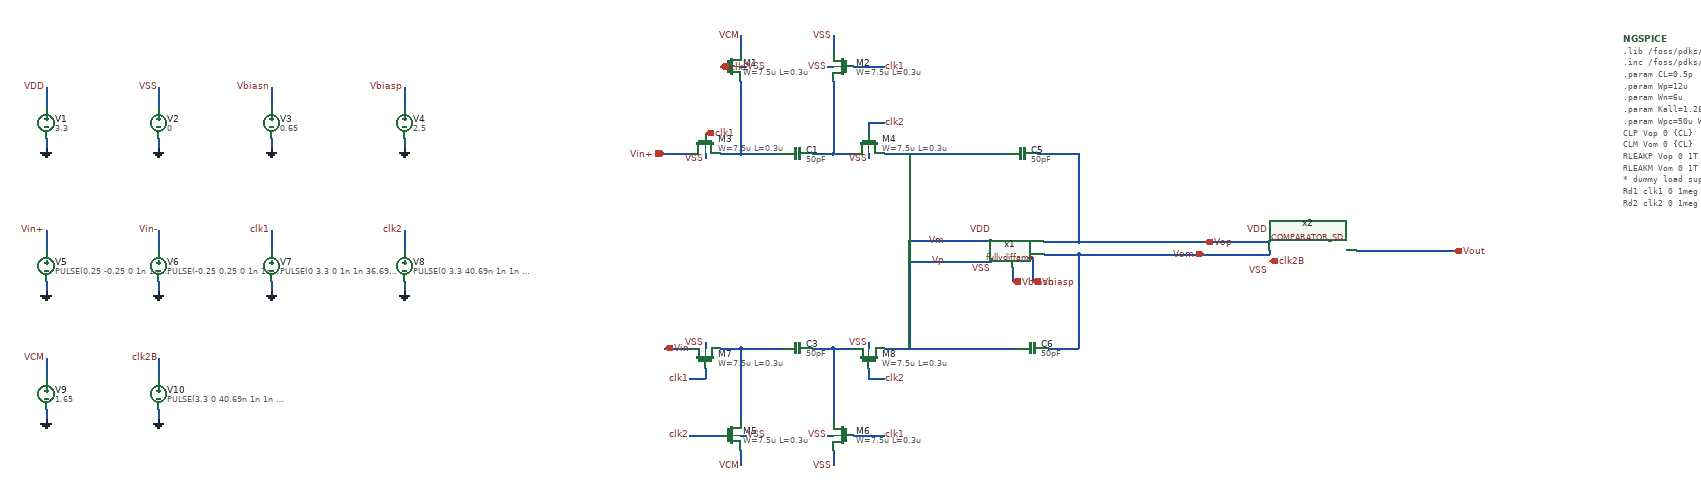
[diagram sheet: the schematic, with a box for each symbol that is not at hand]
v {xschem version=3.4.8RC file_version=1.3}
G {}
K {}
V {}
S {}
F {}
E {}
N 260 -943.75 260 -803.75 {lab=#net1}
N 220 -803.75 260 -803.75 {lab=#net1}
N 260 -803.75 340 -803.75 {lab=#net1}
N 400 -803.75 440 -803.75 {lab=#net2}
N 440 -943.75 440 -803.75 {lab=#net2}
N 440 -803.75 480 -803.75 {lab=#net2}
N 540 -803.75 580 -803.75 {lab=Vm}
N 140 -803.75 160 -803.75 {lab=Vin+}
N 110 -803.75 140 -803.75 {lab=Vin+}
N 510 -863.75 510 -843.75 {lab=clk2}
N 510 -863.75 540 -863.75 {lab=clk2}
N 480 -973.75 540 -973.75 {lab=clk1}
N 440 -1033.75 440 -1003.75 {lab=VSS}
N 260 -1033.75 260 -1003.75 {lab=VCM}
N 260 -423.75 260 -283.75 {lab=#net3}
N 220 -423.75 260 -423.75 {lab=#net3}
N 260 -423.75 340 -423.75 {lab=#net3}
N 400 -423.75 440 -423.75 {lab=#net4}
N 440 -423.75 440 -283.75 {lab=#net4}
N 440 -423.75 480 -423.75 {lab=#net4}
N 540 -423.75 580 -423.75 {lab=Vp}
N 140 -423.75 160 -423.75 {lab=Vin-}
N 110 -423.75 140 -423.75 {lab=Vin-}
N 190 -383.75 190 -363.75 {lab=clk1}
N 160 -363.75 190 -363.75 {lab=clk1}
N 160 -253.75 220 -253.75 {lab=clk2}
N 510 -383.75 510 -363.75 {lab=clk2}
N 510 -363.75 540 -363.75 {lab=clk2}
N 480 -253.75 540 -253.75 {lab=clk1}
N 440 -223.75 440 -193.75 {lab=VSS}
N 260 -223.75 260 -193.75 {lab=VCM}
N 260 -973.75 270 -973.75 {lab=VSS}
N 430 -973.75 440 -973.75 {lab=VSS}
N 190 -803.75 190 -793.75 {lab=VSS}
N 510 -803.75 510 -793.75 {lab=VSS}
N 190 -433.75 190 -423.75 {lab=VSS}
N 510 -433.75 510 -423.75 {lab=VSS}
N 260 -253.75 270 -253.75 {lab=VSS}
N 430 -253.75 440 -253.75 {lab=VSS}
N 580 -803.75 780 -803.75 {lab=Vm}
N 580 -423.75 800 -423.75 {lab=Vp}
N 590 -803.75 590 -633.75 {lab=Vm}
N 590 -633.75 750 -633.75 {lab=Vm}
N 590 -593.75 590 -423.75 {lab=Vp}
N 590 -593.75 750 -593.75 {lab=Vp}
N 750 -598.75 750 -593.75 {lab=Vp}
N 840 -803.75 910 -803.75 {lab=Vop}
N 860 -423.75 920 -423.75 {lab=Vom}
N 852.5 -607.5 920 -607.5 {lab=Vom}
N 851.25 -631.25 918.75 -631.25 {lab=Vop}
N 910 -803.75 920 -803.75 {lab=Vop}
N 918.75 -631.25 920 -631.25 {lab=Vop}
N 920 -803.75 920 -631.25 {lab=Vop}
N 920 -607.5 920 -423.75 {lab=Vom}
N 822.5 -601.25 830 -601.25 {lab=Vbiasp}
N 830 -601.25 830 -553.75 {lab=Vbiasp}
N 790 -581.25 790 -553.75 {lab=Vbiasn}
N 920 -631.25 962.5 -631.25 {lab=Vop}
N 920 -607.5 962.5 -607.5 {lab=Vom}
N 1142.5 -631.25 1292.5 -631.25 {lab=Vop}
N 1292.5 -633.75 1292.5 -631.25 {lab=Vop}
N 1142.5 -607.5 1292.5 -607.5 {lab=Vom}
N 1292.5 -613.75 1292.5 -607.5 {lab=Vom}
N 1462.5 -613.75 1632.5 -613.75 {lab=Vout}
N 1632.5 -613.75 1652.5 -613.75 {lab=Vout}
N 965 -631.25 1012.5 -631.25 {lab=Vop}
N 965 -607.5 1012.5 -607.5 {lab=Vom}
N 962.5 -631.25 965 -631.25 {lab=Vop}
N 962.5 -607.5 965 -607.5 {lab=Vom}
N -1097.5 -933.75 -1097.5 -893.75 {lab=VDD}
N -1097.5 -833.75 -1097.5 -813.75 {lab=0}
N -877.5 -933.75 -877.5 -893.75 {lab=VSS}
N -877.5 -833.75 -877.5 -813.75 {lab=0}
N -657.5 -933.75 -657.5 -893.75 {lab=Vbiasn}
N -657.5 -833.75 -657.5 -813.75 {lab=0}
N -397.5 -933.75 -397.5 -893.75 {lab=Vbiasp}
N -397.5 -833.75 -397.5 -813.75 {lab=0}
N -1097.5 -653.75 -1097.5 -613.75 {lab=Vin+}
N -1097.5 -553.75 -1097.5 -533.75 {lab=0}
N -877.5 -653.75 -877.5 -613.75 {lab=Vin-}
N -877.5 -553.75 -877.5 -533.75 {lab=0}
N -657.5 -653.75 -657.5 -613.75 {lab=clk1}
N -657.5 -553.75 -657.5 -533.75 {lab=0}
N -397.5 -653.75 -397.5 -613.75 {lab=clk2}
N -397.5 -553.75 -397.5 -533.75 {lab=0}
N -1097.5 -403.75 -1097.5 -363.75 {lab=VCM}
N -1097.5 -303.75 -1097.5 -283.75 {lab=0}
N -877.5 -403.75 -877.5 -363.75 {lab=clk2B}
N -877.5 -303.75 -877.5 -283.75 {lab=0}
N 1012.5 -631.25 1142.5 -631.25 {lab=Vop}
N 1012.5 -607.5 1142.5 -607.5 {lab=Vom}
C {symbols/nfet_03v3.sym} 240 -973.75 2 1 {name=M1
L=0.3u
W=7.5u
nf=1
m=1
ad="'int((nf+1)/2) * W/nf * 0.18u'"
pd="'2*int((nf+1)/2) * (W/nf + 0.18u)'"
as="'int((nf+2)/2) * W/nf * 0.18u'"
ps="'2*int((nf+2)/2) * (W/nf + 0.18u)'"
nrd="'0.18u / W'" nrs="'0.18u / W'"
sa=0 sb=0 sd=0
model=nfet_03v3
spiceprefix=X
}
C {symbols/nfet_03v3.sym} 460 -973.75 2 0 {name=M2
L=0.3u
W=7.5u
nf=1
m=1
ad="'int((nf+1)/2) * W/nf * 0.18u'"
pd="'2*int((nf+1)/2) * (W/nf + 0.18u)'"
as="'int((nf+2)/2) * W/nf * 0.18u'"
ps="'2*int((nf+2)/2) * (W/nf + 0.18u)'"
nrd="'0.18u / W'" nrs="'0.18u / W'"
sa=0 sb=0 sd=0
model=nfet_03v3
spiceprefix=X
}
C {symbols/nfet_03v3.sym} 190 -823.75 3 1 {name=M3
L=0.3u
W=7.5u
nf=1
m=1
ad="'int((nf+1)/2) * W/nf * 0.18u'"
pd="'2*int((nf+1)/2) * (W/nf + 0.18u)'"
as="'int((nf+2)/2) * W/nf * 0.18u'"
ps="'2*int((nf+2)/2) * (W/nf + 0.18u)'"
nrd="'0.18u / W'" nrs="'0.18u / W'"
sa=0 sb=0 sd=0
model=nfet_03v3
spiceprefix=X
}
C {symbols/nfet_03v3.sym} 510 -823.75 3 1 {name=M4
L=0.3u
W=7.5u
nf=1
m=1
ad="'int((nf+1)/2) * W/nf * 0.18u'"
pd="'2*int((nf+1)/2) * (W/nf + 0.18u)'"
as="'int((nf+2)/2) * W/nf * 0.18u'"
ps="'2*int((nf+2)/2) * (W/nf + 0.18u)'"
nrd="'0.18u / W'" nrs="'0.18u / W'"
sa=0 sb=0 sd=0
model=nfet_03v3
spiceprefix=X
}
C {capa.sym} 370 -803.75 1 1 {name=C1
m=1
value=50pF
footprint=1206
device="ceramic capacitor"}
C {ipin.sym} 110 -803.75 0 0 {name=p3 lab=Vin+}
C {lab_pin.sym} 540 -973.75 2 0 {name=p1 sig_type=std_logic lab=clk1}
C {lab_pin.sym} 540 -863.75 2 0 {name=p5 sig_type=std_logic lab=clk2}
C {symbols/nfet_03v3.sym} 240 -253.75 0 0 {name=M5
L=0.3u
W=7.5u
nf=1
m=1
ad="'int((nf+1)/2) * W/nf * 0.18u'"
pd="'2*int((nf+1)/2) * (W/nf + 0.18u)'"
as="'int((nf+2)/2) * W/nf * 0.18u'"
ps="'2*int((nf+2)/2) * (W/nf + 0.18u)'"
nrd="'0.18u / W'" nrs="'0.18u / W'"
sa=0 sb=0 sd=0
model=nfet_03v3
spiceprefix=X
}
C {symbols/nfet_03v3.sym} 460 -253.75 0 1 {name=M6
L=0.3u
W=7.5u
nf=1
m=1
ad="'int((nf+1)/2) * W/nf * 0.18u'"
pd="'2*int((nf+1)/2) * (W/nf + 0.18u)'"
as="'int((nf+2)/2) * W/nf * 0.18u'"
ps="'2*int((nf+2)/2) * (W/nf + 0.18u)'"
nrd="'0.18u / W'" nrs="'0.18u / W'"
sa=0 sb=0 sd=0
model=nfet_03v3
spiceprefix=X
}
C {symbols/nfet_03v3.sym} 190 -403.75 3 0 {name=M7
L=0.3u
W=7.5u
nf=1
m=1
ad="'int((nf+1)/2) * W/nf * 0.18u'"
pd="'2*int((nf+1)/2) * (W/nf + 0.18u)'"
as="'int((nf+2)/2) * W/nf * 0.18u'"
ps="'2*int((nf+2)/2) * (W/nf + 0.18u)'"
nrd="'0.18u / W'" nrs="'0.18u / W'"
sa=0 sb=0 sd=0
model=nfet_03v3
spiceprefix=X
}
C {symbols/nfet_03v3.sym} 510 -403.75 3 0 {name=M8
L=0.3u
W=7.5u
nf=1
m=1
ad="'int((nf+1)/2) * W/nf * 0.18u'"
pd="'2*int((nf+1)/2) * (W/nf + 0.18u)'"
as="'int((nf+2)/2) * W/nf * 0.18u'"
ps="'2*int((nf+2)/2) * (W/nf + 0.18u)'"
nrd="'0.18u / W'" nrs="'0.18u / W'"
sa=0 sb=0 sd=0
model=nfet_03v3
spiceprefix=X
}
C {capa.sym} 370 -423.75 1 0 {name=C3
m=1
value=50pF
footprint=1206
device="ceramic capacitor"}
C {ipin.sym} 110 -423.75 2 1 {name=p6 lab=Vin-}
C {lab_pin.sym} 540 -253.75 0 1 {name=p7 sig_type=std_logic lab=clk1}
C {lab_pin.sym} 160 -363.75 2 1 {name=p8 sig_type=std_logic lab=clk1}
C {lab_pin.sym} 160 -253.75 2 1 {name=p9 sig_type=std_logic lab=clk2}
C {lab_pin.sym} 540 -363.75 0 1 {name=p10 sig_type=std_logic lab=clk2}
C {lab_pin.sym} 270 -973.75 2 0 {name=p13 sig_type=std_logic lab=VSS}
C {lab_pin.sym} 430 -973.75 0 0 {name=p14 sig_type=std_logic lab=VSS}
C {lab_pin.sym} 190 -793.75 3 0 {name=p15 sig_type=std_logic lab=VSS}
C {lab_pin.sym} 510 -793.75 3 0 {name=p16 sig_type=std_logic lab=VSS}
C {lab_pin.sym} 190 -433.75 1 0 {name=p17 sig_type=std_logic lab=VSS}
C {lab_pin.sym} 510 -433.75 1 0 {name=p18 sig_type=std_logic lab=VSS}
C {lab_pin.sym} 270 -253.75 2 0 {name=p19 sig_type=std_logic lab=VSS}
C {lab_pin.sym} 430 -253.75 0 0 {name=p20 sig_type=std_logic lab=VSS}
C {capa.sym} 810 -803.75 3 0 {name=C5
m=1
value=50pF
footprint=1206
device="ceramic capacitor"}
C {capa.sym} 830 -423.75 3 0 {name=C6
m=1
value=50pF
footprint=1206
device="ceramic capacitor"}
C {opin.sym} 1165 -631.25 3 0 {name=p11 lab=Vop}
C {opin.sym} 1166.25 -607.5 3 1 {name=p12 lab=Vom}
C {lab_pin.sym} 750 -578.75 0 0 {name=p23 sig_type=std_logic lab=VSS}
C {lab_pin.sym} 750 -653.75 0 0 {name=p24 sig_type=std_logic lab=VDD}
C {lab_pin.sym} 440 -193.75 3 0 {name=p38 sig_type=std_logic lab=VSS}
C {lab_pin.sym} 440 -1033.75 1 0 {name=p39 sig_type=std_logic lab=VSS}
C {ipin.sym} 190 -843.75 3 1 {name=p41 lab=clk1}
C {ipin.sym} 220 -973.75 2 1 {name=p2 lab=clk2}
C {ipin.sym} 790 -553.75 1 1 {name=p4 lab=Vbiasn}
C {ipin.sym} 830 -553.75 1 1 {name=p42 lab=Vbiasp}
C {lab_pin.sym} 660 -633.75 1 0 {name=p33 sig_type=std_logic lab=Vm}
C {lab_pin.sym} 660 -593.75 3 0 {name=p34 sig_type=std_logic lab=Vp}
C {fully_differential_amplifier/fullydiffamp.sym} 810 -528.75 0 0 {name=x1}
C {lab_pin.sym} 1292.5 -653.75 0 0 {name=p46 sig_type=std_logic lab=VDD}
C {lab_pin.sym} 1292.5 -573.75 0 0 {name=p47 sig_type=std_logic lab=VSS}
C {opin.sym} 1652.5 -613.75 0 0 {name=p52 lab=Vout}
C {ipin.sym} 1292.5 -593.75 2 1 {name=p57 lab=clk2B}
C {lab_pin.sym} 260 -1033.75 1 0 {name=p36 sig_type=std_logic lab=VCM}
C {lab_pin.sym} 260 -193.75 3 0 {name=p21 sig_type=std_logic lab=VCM}
C {vsource.sym} -1097.5 -863.75 0 0 {name=V1 value=3.3 savecurrent=false}
C {gnd.sym} -1097.5 -813.75 0 0 {name=l5 lab=0}
C {vsource.sym} -877.5 -863.75 0 0 {name=V2 value=0 savecurrent=false}
C {gnd.sym} -877.5 -813.75 0 0 {name=l6 lab=0}
C {vsource.sym} -657.5 -863.75 0 0 {name=V3 value=0.65 savecurrent=false}
C {gnd.sym} -657.5 -813.75 0 0 {name=l7 lab=0}
C {vsource.sym} -397.5 -863.75 0 0 {name=V4 value=2.5 savecurrent=false}
C {gnd.sym} -397.5 -813.75 0 0 {name=l8 lab=0}
C {vsource.sym} -1097.5 -583.75 0 0 {name=V5 value="PULSE(0.25 -0.25 0 1n 1n 5u 10u)" savecurrent=false}
C {gnd.sym} -1097.5 -533.75 0 0 {name=l9 lab=0}
C {vsource.sym} -877.5 -583.75 0 0 {name=V6 value="PULSE(-0.25 0.25 0 1n 1n 5u 10u)" savecurrent=false}
C {gnd.sym} -877.5 -533.75 0 0 {name=l10 lab=0}
C {vsource.sym} -657.5 -583.75 0 0 {name=V7 value="PULSE(0 3.3 0 1n 1n 36.69n 81.38n)" savecurrent=false}
C {gnd.sym} -657.5 -533.75 0 0 {name=l11 lab=0}
C {vsource.sym} -397.5 -583.75 0 0 {name=V8 value="PULSE(0 3.3 40.69n 1n 1n 36.69n 81.38n)" savecurrent=false}
C {gnd.sym} -397.5 -533.75 0 0 {name=l12 lab=0}
C {lab_pin.sym} -1097.5 -933.75 1 0 {name=p25 sig_type=std_logic lab=VDD}
C {lab_pin.sym} -877.5 -933.75 1 0 {name=p26 sig_type=std_logic lab=VSS
}
C {lab_pin.sym} -657.5 -933.75 1 0 {name=p27 sig_type=std_logic lab=Vbiasn
}
C {lab_pin.sym} -397.5 -933.75 1 0 {name=p28 sig_type=std_logic lab=Vbiasp
}
C {lab_pin.sym} -1097.5 -653.75 1 0 {name=p29 sig_type=std_logic lab=Vin+}
C {lab_pin.sym} -877.5 -653.75 1 0 {name=p30 sig_type=std_logic lab=Vin-}
C {lab_pin.sym} -657.5 -653.75 1 0 {name=p31 sig_type=std_logic lab=clk1}
C {lab_pin.sym} -397.5 -653.75 1 0 {name=p32 sig_type=std_logic lab=clk2}
C {vsource.sym} -1097.5 -333.75 0 0 {name=V9 value=1.65 savecurrent=false}
C {gnd.sym} -1097.5 -283.75 0 0 {name=l1 lab=0}
C {lab_pin.sym} -1097.5 -403.75 1 0 {name=p35 sig_type=std_logic lab=VCM}
C {devices/code_shown.sym} 1983.75 -1027.5 0 0 {name=NGSPICE only_toplevel=true
value="
.lib /foss/pdks/gf180mcuD/libs.tech/ngspice/sm141064.ngspice typical
.inc /foss/pdks/gf180mcuD/libs.tech/ngspice/design.ngspice

.param CL=0.5p
.param Wp=12u
.param Wn=6u
.param Kall=1.28u
.param Wpc=50u Wnc=2u Wsc=2*Wp Lc=10u
CLP Vop 0 \{CL\}
CLM Vom 0 \{CL\}
RLEAKP Vop 0 1T
RLEAKM Vom 0 1T

* dummy load supaya tiap node punya DC path ke ground
Rd1 clk1  0 1meg
Rd2 clk2  0 1meg

.control
set color0=white
set color1=black
tran 2n 200u
let vicm_ota = (v(Vp)+v(Vm))/2
let vid_ota  = v(Vp)-v(Vm)
* --- window ala paper ---
plot v(clk1) v(clk2)          $ window 1: non-overlapping clocks
plot v(Vin+) v(Vin-)          $ window 2: input diferensial
plot v(Vop) v(Vom)            $ window 3: output OTA (single-ended)
plot v(Vop)-v(Vom) v(Vout)           $ window 4: output integrator (diferensial) -> segitiga
plot v(Vp) v(Vm)
plot vicm_ota
plot vid_ota
.endc
.end
"}
C {latched_comparator/COMPARATOR_SD.sym} 1272.5 -453.75 0 0 {name=x2}
C {vsource.sym} -877.5 -333.75 0 0 {name=V10 value="PULSE(3.3 0 40.69n 1n 1n 36.69n 81.38n)" savecurrent=false}
C {gnd.sym} -877.5 -283.75 0 0 {name=l2 lab=0}
C {lab_pin.sym} -877.5 -403.75 1 0 {name=p22 sig_type=std_logic lab=clk2B}
